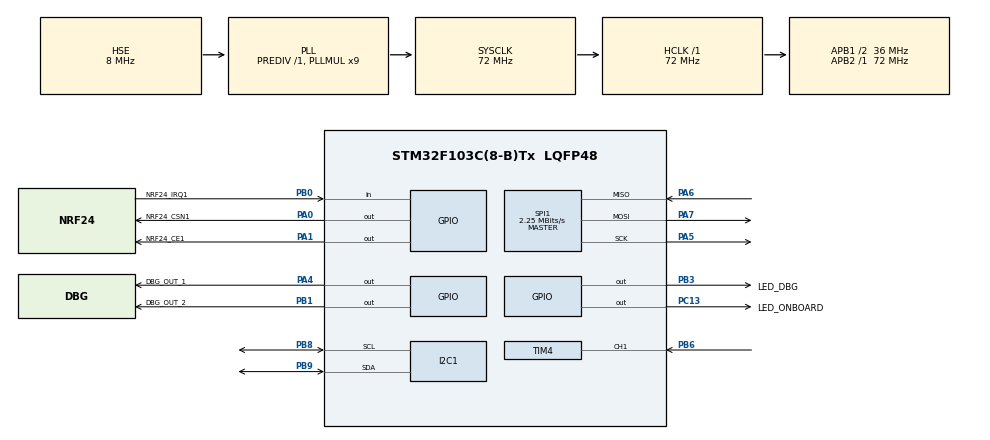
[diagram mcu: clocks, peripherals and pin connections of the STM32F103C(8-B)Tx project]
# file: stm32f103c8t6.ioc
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Mcu.Family=STM32F1
Mcu.Name=STM32F103C(8-B)Tx
Mcu.Package=LQFP48
Mcu.UserConstants=DelayCheckingPeriod,(100 - 1);envelop_timer_prescaler,(72 - 1);max_period,(65535-1)
NVIC.PriorityGroup=NVIC_PRIORITYGROUP_4
NVIC.SPI1_IRQn=true\:0\:0\:false\:false\:true
NVIC.TIM3_IRQn=true\:0\:0\:false\:false\:true
NVIC.TIM4_IRQn=true\:0\:0\:false\:false\:true
PA0-WKUP.GPIO_Label=NRF24_CSN1
PA0-WKUP.GPIO_Speed=GPIO_SPEED_FREQ_HIGH
PA0-WKUP.Signal=GPIO_Output
PA1.GPIO_Label=NRF24_CE1
PA1.GPIO_Speed=GPIO_SPEED_FREQ_HIGH
PA1.Signal=GPIO_Output
PA13.Mode=Serial_Wire
PA13.Signal=SYS_JTMS-SWDIO
PA14.Mode=Serial_Wire
PA14.Signal=SYS_JTCK-SWCLK
PA4.GPIO_Label=DBG_OUT_1
PA4.GPIO_Speed=GPIO_SPEED_FREQ_HIGH
PA4.PinState=GPIO_PIN_RESET
PA4.Signal=GPIO_Output
PA5.Mode=Full_Duplex_Master
PA5.Signal=SPI1_SCK
PA6.Mode=Full_Duplex_Master
PA6.Signal=SPI1_MISO
PA7.Mode=Full_Duplex_Master
PA7.Signal=SPI1_MOSI
PB0.GPIO_Label=NRF24_IRQ1
PB0.GPIO_PuPd=GPIO_PULLUP
PB0.Signal=GPIO_Input
PB1.GPIO_Label=DBG_OUT_2
PB1.GPIO_Speed=GPIO_SPEED_FREQ_HIGH
PB1.Signal=GPIO_Output
PB3.GPIO_Label=LED_DBG
PB3.GPIO_Speed=GPIO_SPEED_FREQ_HIGH
PB3.Signal=GPIO_Output
PB6.Signal=S_TIM4_CH1
PB8.Mode=I2C
PB8.Signal=I2C1_SCL
PB9.Mode=I2C
PB9.Signal=I2C1_SDA
PC13-TAMPER-RTC.GPIO_Label=LED_ONBOARD
PC13-TAMPER-RTC.GPIO_Speed=GPIO_SPEED_FREQ_LOW
PC13-TAMPER-RTC.Signal=GPIO_Output
PD0-OSC_IN.Mode=HSE-External-Oscillator
PD0-OSC_IN.Signal=RCC_OSC_IN
PD1-OSC_OUT.Mode=HSE-External-Oscillator
PD1-OSC_OUT.Signal=RCC_OSC_OUT
ProjectManager.HeapSize=0x200
ProjectManager.StackSize=0x400
ProjectManager.TargetToolchain=SW4STM32
RCC.ADCPresc=RCC_ADCPCLK2_DIV6
RCC.AHBFreq_Value=72000000
RCC.APB1CLKDivider=RCC_HCLK_DIV2
RCC.APB1Freq_Value=36000000
RCC.APB1TimFreq_Value=72000000
RCC.APB2Freq_Value=72000000
RCC.APB2TimFreq_Value=72000000
RCC.HCLKFreq_Value=72000000
RCC.HSIState=RCC_HSI_ON
RCC.PLLMUL=RCC_PLL_MUL9
RCC.PLLSourceVirtual=RCC_PLLSOURCE_HSE
RCC.SYSCLKFreq_VALUE=72000000
RCC.SYSCLKSource=RCC_SYSCLKSOURCE_PLLCLK
RCC.USBFreq_Value=48000000
RCC.USBPrescaler=RCC_USBCLKSOURCE_PLL_DIV1_5
SH.S_TIM4_CH1.0=TIM4_CH1,Input_Capture1_from_TI1
SH.S_TIM4_CH1.1=TIM4_CH1,Input_Capture2_from_TI1
SH.S_TIM4_CH1.2=TIM4_CH1,TriggerSource_TI1FP1
SPI1.BaudRatePrescaler=SPI_BAUDRATEPRESCALER_32
SPI1.CalculateBaudRate=2.25 MBits/s
SPI1.Mode=SPI_MODE_MASTER
TIM2.Period=71
TIM3.Period=DelayCheckingPeriod
TIM3.Prescaler=envelop_timer_prescaler
TIM3.TIM_MasterOutputTrigger=TIM_TRGO_UPDATE
TIM3.TIM_MasterSlaveMode=TIM_MASTERSLAVEMODE_DISABLE
TIM4.Channel-Input_Capture2_from_TI1=TIM_CHANNEL_2
TIM4.Period=65535
TIM4.Prescaler=envelop_timer_prescaler
TIM4.TIM_MasterOutputTrigger=TIM_TRGO_OC1
VP_CRC_VS_CRC.Mode=CRC_Activate
VP_TIM2_VS_ClockSourceINT.Mode=Internal
VP_TIM3_VS_ClockSourceINT.Mode=Internal
VP_TIM4_VS_ClockSourceINT.Mode=Internal
VP_TIM4_VS_ControllerModeReset.Mode=Reset Mode
board=stm32f103c8t6

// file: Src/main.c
/**
  ******************************************************************************
  * File Name          : main.c
  * Description        : Main program body
  ******************************************************************************
  *
  * COPYRIGHT(c) 2016 STMicroelectronics
  *
  * Redistribution and use in source and binary forms, with or without modification,
  * are permitted provided that the following conditions are met:
  *   1. Redistributions of source code must retain the above copyright notice,
  *      this list of conditions and the following disclaimer.
  *   2. Redistributions in binary form must reproduce the above copyright notice,
  *      this list of conditions and the following disclaimer in the documentation
  *      and/or other materials provided with the distribution.
  *   3. Neither the name of STMicroelectronics nor the names of its contributors
  *      may be used to endorse or promote products derived from this software
  *      without specific prior written permission.
  *
  * THIS SOFTWARE IS PROVIDED BY THE COPYRIGHT HOLDERS AND CONTRIBUTORS "AS IS"
  * AND ANY EXPRESS OR IMPLIED WARRANTIES, INCLUDING, BUT NOT LIMITED TO, THE
  * IMPLIED WARRANTIES OF MERCHANTABILITY AND FITNESS FOR A PARTICULAR PURPOSE ARE
  * DISCLAIMED. IN NO EVENT SHALL THE COPYRIGHT HOLDER OR CONTRIBUTORS BE LIABLE
  * FOR ANY DIRECT, INDIRECT, INCIDENTAL, SPECIAL, EXEMPLARY, OR CONSEQUENTIAL
  * DAMAGES (INCLUDING, BUT NOT LIMITED TO, PROCUREMENT OF SUBSTITUTE GOODS OR
  * SERVICES; LOSS OF USE, DATA, OR PROFITS; OR BUSINESS INTERRUPTION) HOWEVER
  * CAUSED AND ON ANY THEORY OF LIABILITY, WHETHER IN CONTRACT, STRICT LIABILITY,
  * OR TORT (INCLUDING NEGLIGENCE OR OTHERWISE) ARISING IN ANY WAY OUT OF THE USE
  * OF THIS SOFTWARE, EVEN IF ADVISED OF THE POSSIBILITY OF SUCH DAMAGE.
  *
  ******************************************************************************
  */
#include "stm32f1xx_hal.h"

/* USER CODE BEGIN Includes */
#include <stdbool.h>
#include "infrared.h"
#include "sensor.h"
#include "se8r01.h"
#include "MPU6050.h"
#include "common.h"
#define USE_OLD_MAPPING 1

// TODO: cleanup when done debugging
/* USER CODE END Includes */

CRC_HandleTypeDef hcrc;

I2C_HandleTypeDef hi2c1;

SPI_HandleTypeDef hspi1;

TIM_HandleTypeDef htim2;
TIM_HandleTypeDef htim3;
TIM_HandleTypeDef htim4;

/* USER CODE BEGIN PV */
/* Private variables ---------------------------------------------------------*/
/// parameters for receiver ===================
const GPIO_TypeDef * IR_IN_Gpio_Port = GPIOB;
const uint16_t IR_IN_Gpio_Pin = GPIO_PIN_10;

TIM_HandleTypeDef* ptim_input_capture = &htim4;
TIM_HandleTypeDef* ptim_data_read = &htim3;
TIM_HandleTypeDef* phtim_delay = &htim2;

extern const bool _is_direct_logic;
const bool _debug = true;

extern GPIO_TypeDef * GPIO_LED_PORT;
extern uint16_t GPIO_LED_PIN;
/// ===========================================

/* USER CODE END PV */

void SystemClock_Config(void);
void Error_Handler(void);
static void MX_GPIO_Init(void);
static void MX_CRC_Init(void);
static void MX_SPI1_Init(void);
static void MX_TIM3_Init(void);
static void MX_TIM4_Init(void);
static void MX_TIM2_Init(void);
static void MX_I2C1_Init(void);

/* USER CODE BEGIN PFP */
/* Private function prototypes -----------------------------------------------*/
HAL_StatusTypeDef HAL_TIM_IC_PWM_Start_IT (const TIM_HandleTypeDef *htim);
HAL_StatusTypeDef HAL_TIM_IC_PWM_Stop_IT (const TIM_HandleTypeDef *htim);
void send_data_uart();
void setup_infrared_input_gpio();

extern uint8_t rx_buf[TX_PLOAD_WIDTH];
extern uint8_t tx_buf[TX_PLOAD_WIDTH];
extern RadioMessage rx_message;
extern RadioMessage tx_message;

extern NRF_Module default_module;
extern NRF_Module data_module;

extern RadioDevInfo radiodevinfo;
extern SensorData sensordata;
BeamerData beamerdata = {0};
IMUData imudata = {0};

/* USER CODE END PFP */

/* USER CODE BEGIN 0 */
/// ======================= USART stuff =======================
HAL_StatusTypeDef status;
extern DataFrame_t rx_data_frame;

const char mode = 'r'; // 't'
/* USER CODE END 0 */

int main(void)
{

  /* MCU Configuration----------------------------------------------------------*/
  /* Reset of all peripherals, Initializes the Flash interface and the Systick. */
  HAL_Init();

  /* Configure the system clock */
  SystemClock_Config();

  /* Initialize all configured peripherals */
  MX_GPIO_Init();
  MX_CRC_Init();
  MX_SPI1_Init();
  MX_TIM3_Init();
  MX_TIM4_Init();
  MX_TIM2_Init();
  MX_I2C1_Init();

  /* USER CODE BEGIN 2 */
  setup_infrared_input_gpio();

  bool use_radio = true;

  if(use_radio){
    configure_gpio_radio();
  }

    //TODO: setting the timer. merge with TIM_Init

    //// start usec delay timer
    HAL_TIM_Base_Start(&htim2);

    bool enable_IR_timers = true;//TODO
    if(enable_IR_timers){
        setup_ic_timer();
        HAL_TIM_Base_Start_IT(ptim_data_read);
        HAL_TIM_IC_PWM_Start_IT(ptim_input_capture);
    }
  /* USER CODE END 2 */

  /* Infinite loop */
  /* USER CODE BEGIN WHILE */

    // use identical bytes
    bool is_transmitter = (mode =='t');
    bool is_receiver = !is_transmitter;

    if(use_radio){
      setup(&default_module);
    }

    //nrf_without_this_interrupts_not_work();
    HAL_Delay(100);

    if (MPU6050_testConnection()){
        HAL_GPIO_WritePin (LED_ONBOARD_GPIO_Port, LED_ONBOARD_Pin, HIGH);
    }
    else{
          HAL_GPIO_WritePin (LED_ONBOARD_GPIO_Port, LED_ONBOARD_Pin, LOW);
    }

    while (1)
    {

        /*
        GPIO_PinState state = HAL_GPIO_ReadPin (GPIOB, GPIO_PIN_6);
        if(state == HIGH){
            HAL_GPIO_WritePin (GPIOB, GPIO_PIN_11, HIGH);
            HAL_GPIO_WritePin (LED_ONBOARD_GPIO_Port, LED_ONBOARD_Pin, HIGH);
        }
        else{
            HAL_GPIO_WritePin (GPIOB, GPIO_PIN_11, LOW);
            HAL_GPIO_WritePin (LED_ONBOARD_GPIO_Port, LED_ONBOARD_Pin, HIGH);
        }
        */

        if(use_radio)
        {
            if(is_receiver){
                RXX(&default_module);// - this is called on IRQ
            }
            else if(is_transmitter){
                //=================== prepare message for sending
                // Determine source of packet
                radio_tx_set_message_header(WhoAmI_Sensor, Dest_UsbDevice,Typ_SensorData);

                SingleBeamerData singlebeamdata;
                singlebeamdata.angle = 124;
                singlebeamdata.beamer_id = 1;

                beamerdata.beamer_data_array[0] = singlebeamdata;

                radio_tx_set_sensordata(&sensordata);
                //=====================

                TXX(&default_module);
                HAL_Delay(30);
            }
        }

  /* USER CODE END WHILE */

    }

}

/** System Clock Configuration
*/
void SystemClock_Config(void)
{

  RCC_OscInitTypeDef RCC_OscInitStruct;
  RCC_ClkInitTypeDef RCC_ClkInitStruct;

  RCC_OscInitStruct.OscillatorType = RCC_OSCILLATORTYPE_HSE;
  RCC_OscInitStruct.HSEState = RCC_HSE_ON;
  RCC_OscInitStruct.HSEPredivValue = RCC_HSE_PREDIV_DIV1;
  RCC_OscInitStruct.PLL.PLLState = RCC_PLL_ON;
  RCC_OscInitStruct.PLL.PLLSource = RCC_PLLSOURCE_HSE;
  RCC_OscInitStruct.PLL.PLLMUL = RCC_PLL_MUL9;
  if (HAL_RCC_OscConfig(&RCC_OscInitStruct) != HAL_OK)
  {
    Error_Handler();
  }

  RCC_ClkInitStruct.ClockType = RCC_CLOCKTYPE_HCLK|RCC_CLOCKTYPE_SYSCLK
                              |RCC_CLOCKTYPE_PCLK1|RCC_CLOCKTYPE_PCLK2;
  RCC_ClkInitStruct.SYSCLKSource = RCC_SYSCLKSOURCE_PLLCLK;
  RCC_ClkInitStruct.AHBCLKDivider = RCC_SYSCLK_DIV1;
  RCC_ClkInitStruct.APB1CLKDivider = RCC_HCLK_DIV2;
  RCC_ClkInitStruct.APB2CLKDivider = RCC_HCLK_DIV1;
  if (HAL_RCC_ClockConfig(&RCC_ClkInitStruct, FLASH_LATENCY_2) != HAL_OK)
  {
    Error_Handler();
  }

  HAL_SYSTICK_Config(HAL_RCC_GetHCLKFreq()/1000);

  HAL_SYSTICK_CLKSourceConfig(SYSTICK_CLKSOURCE_HCLK);

  /* SysTick_IRQn interrupt configuration */
  HAL_NVIC_SetPriority(SysTick_IRQn, 0, 0);
}

/* CRC init function */
static void MX_CRC_Init(void)
{

  hcrc.Instance = CRC;
  if (HAL_CRC_Init(&hcrc) != HAL_OK)
  {
    Error_Handler();
  }

}

/* I2C1 init function */
static void MX_I2C1_Init(void)
{

  hi2c1.Instance = I2C1;
  hi2c1.Init.ClockSpeed = 100000;
  hi2c1.Init.DutyCycle = I2C_DUTYCYCLE_2;
  hi2c1.Init.OwnAddress1 = 0;
  hi2c1.Init.AddressingMode = I2C_ADDRESSINGMODE_7BIT;
  hi2c1.Init.DualAddressMode = I2C_DUALADDRESS_DISABLE;
  hi2c1.Init.OwnAddress2 = 0;
  hi2c1.Init.GeneralCallMode = I2C_GENERALCALL_DISABLE;
  hi2c1.Init.NoStretchMode = I2C_NOSTRETCH_DISABLE;
  if (HAL_I2C_Init(&hi2c1) != HAL_OK)
  {
    Error_Handler();
  }

}

/* SPI1 init function */
static void MX_SPI1_Init(void)
{

  hspi1.Instance = SPI1;
  hspi1.Init.Mode = SPI_MODE_MASTER;
  hspi1.Init.Direction = SPI_DIRECTION_2LINES;
  hspi1.Init.DataSize = SPI_DATASIZE_8BIT;
  hspi1.Init.CLKPolarity = SPI_POLARITY_LOW;
  hspi1.Init.CLKPhase = SPI_PHASE_1EDGE;
  hspi1.Init.NSS = SPI_NSS_SOFT;
  hspi1.Init.BaudRatePrescaler = SPI_BAUDRATEPRESCALER_4;
  hspi1.Init.FirstBit = SPI_FIRSTBIT_MSB;
  hspi1.Init.TIMode = SPI_TIMODE_DISABLE;
  hspi1.Init.CRCCalculation = SPI_CRCCALCULATION_DISABLE;
  hspi1.Init.CRCPolynomial = 10;
  if (HAL_SPI_Init(&hspi1) != HAL_OK)
  {
    Error_Handler();
  }

}

/* TIM2 init function */
static void MX_TIM2_Init(void)
{

  TIM_ClockConfigTypeDef sClockSourceConfig;
  TIM_MasterConfigTypeDef sMasterConfig;

  htim2.Instance = TIM2;
  htim2.Init.Prescaler = 0;
  htim2.Init.CounterMode = TIM_COUNTERMODE_UP;
  htim2.Init.Period = 71;
  htim2.Init.ClockDivision = TIM_CLOCKDIVISION_DIV1;
  if (HAL_TIM_Base_Init(&htim2) != HAL_OK)
  {
    Error_Handler();
  }

  sClockSourceConfig.ClockSource = TIM_CLOCKSOURCE_INTERNAL;
  if (HAL_TIM_ConfigClockSource(&htim2, &sClockSourceConfig) != HAL_OK)
  {
    Error_Handler();
  }

  sMasterConfig.MasterOutputTrigger = TIM_TRGO_RESET;
  sMasterConfig.MasterSlaveMode = TIM_MASTERSLAVEMODE_DISABLE;
  if (HAL_TIMEx_MasterConfigSynchronization(&htim2, &sMasterConfig) != HAL_OK)
  {
    Error_Handler();
  }

}

/* TIM3 init function */
static void MX_TIM3_Init(void)
{

  TIM_ClockConfigTypeDef sClockSourceConfig;
  TIM_MasterConfigTypeDef sMasterConfig;

  htim3.Instance = TIM3;
  htim3.Init.Prescaler = (72-1);
  htim3.Init.CounterMode = TIM_COUNTERMODE_UP;
  htim3.Init.Period = 100-1;
  htim3.Init.ClockDivision = TIM_CLOCKDIVISION_DIV1;
  if (HAL_TIM_Base_Init(&htim3) != HAL_OK)
  {
    Error_Handler();
  }

  sClockSourceConfig.ClockSource = TIM_CLOCKSOURCE_INTERNAL;
  if (HAL_TIM_ConfigClockSource(&htim3, &sClockSourceConfig) != HAL_OK)
  {
    Error_Handler();
  }

  sMasterConfig.MasterOutputTrigger = TIM_TRGO_UPDATE;
  sMasterConfig.MasterSlaveMode = TIM_MASTERSLAVEMODE_DISABLE;
  if (HAL_TIMEx_MasterConfigSynchronization(&htim3, &sMasterConfig) != HAL_OK)
  {
    Error_Handler();
  }

}

/* TIM4 init function */
static void MX_TIM4_Init(void)
{

  TIM_ClockConfigTypeDef sClockSourceConfig;
  TIM_SlaveConfigTypeDef sSlaveConfig;
  TIM_MasterConfigTypeDef sMasterConfig;
  TIM_IC_InitTypeDef sConfigIC;

  htim4.Instance = TIM4;
  htim4.Init.Prescaler = 72-1;
  htim4.Init.CounterMode = TIM_COUNTERMODE_UP;
  htim4.Init.Period = 65535;
  htim4.Init.ClockDivision = TIM_CLOCKDIVISION_DIV1;
  if (HAL_TIM_Base_Init(&htim4) != HAL_OK)
  {
    Error_Handler();
  }

  sClockSourceConfig.ClockSource = TIM_CLOCKSOURCE_INTERNAL;
  if (HAL_TIM_ConfigClockSource(&htim4, &sClockSourceConfig) != HAL_OK)
  {
    Error_Handler();
  }

  if (HAL_TIM_IC_Init(&htim4) != HAL_OK)
  {
    Error_Handler();
  }

  sSlaveConfig.SlaveMode = TIM_SLAVEMODE_RESET;
  sSlaveConfig.InputTrigger = TIM_TS_TI1FP1;
  sSlaveConfig.TriggerPolarity = TIM_INPUTCHANNELPOLARITY_FALLING;
  sSlaveConfig.TriggerFilter = 0;
  if (HAL_TIM_SlaveConfigSynchronization(&htim4, &sSlaveConfig) != HAL_OK)
  {
    Error_Handler();
  }

  sMasterConfig.MasterOutputTrigger = TIM_TRGO_OC1;
  sMasterConfig.MasterSlaveMode = TIM_MASTERSLAVEMODE_DISABLE;
  if (HAL_TIMEx_MasterConfigSynchronization(&htim4, &sMasterConfig) != HAL_OK)
  {
    Error_Handler();
  }

  sConfigIC.ICPolarity = TIM_INPUTCHANNELPOLARITY_FALLING;
  sConfigIC.ICSelection = TIM_ICSELECTION_DIRECTTI;
  sConfigIC.ICPrescaler = TIM_ICPSC_DIV1;
  sConfigIC.ICFilter = 0;
  if (HAL_TIM_IC_ConfigChannel(&htim4, &sConfigIC, TIM_CHANNEL_1) != HAL_OK)
  {
    Error_Handler();
  }

  sConfigIC.ICPolarity = TIM_INPUTCHANNELPOLARITY_RISING;
  sConfigIC.ICSelection = TIM_ICSELECTION_INDIRECTTI;
  if (HAL_TIM_IC_ConfigChannel(&htim4, &sConfigIC, TIM_CHANNEL_2) != HAL_OK)
  {
    Error_Handler();
  }

}

/** Configure pins as
        * Analog
        * Input
        * Output
        * EVENT_OUT
        * EXTI
*/
static void MX_GPIO_Init(void)
{

  GPIO_InitTypeDef GPIO_InitStruct;

  /* GPIO Ports Clock Enable */
  __HAL_RCC_GPIOC_CLK_ENABLE();
  __HAL_RCC_GPIOD_CLK_ENABLE();
  __HAL_RCC_GPIOA_CLK_ENABLE();
  __HAL_RCC_GPIOB_CLK_ENABLE();

  /*Configure GPIO pin Output Level */
  HAL_GPIO_WritePin(LED_ONBOARD_GPIO_Port, LED_ONBOARD_Pin, GPIO_PIN_RESET);

  /*Configure GPIO pin Output Level */
  HAL_GPIO_WritePin(GPIOB, GPIO_PIN_11|LED_DBG_Pin, GPIO_PIN_RESET);

  /*Configure GPIO pin : LED_ONBOARD_Pin */
  GPIO_InitStruct.Pin = LED_ONBOARD_Pin;
  GPIO_InitStruct.Mode = GPIO_MODE_OUTPUT_PP;
  GPIO_InitStruct.Speed = GPIO_SPEED_FREQ_LOW;
  HAL_GPIO_Init(LED_ONBOARD_GPIO_Port, &GPIO_InitStruct);

  /*Configure GPIO pin : PB10 */
  GPIO_InitStruct.Pin = GPIO_PIN_10;
  GPIO_InitStruct.Mode = GPIO_MODE_INPUT;
  GPIO_InitStruct.Pull = GPIO_NOPULL;
  HAL_GPIO_Init(GPIOB, &GPIO_InitStruct);

  /*Configure GPIO pin : PB11 */
  GPIO_InitStruct.Pin = GPIO_PIN_11;
  GPIO_InitStruct.Mode = GPIO_MODE_OUTPUT_PP;
  GPIO_InitStruct.Speed = GPIO_SPEED_FREQ_HIGH;
  HAL_GPIO_Init(GPIOB, &GPIO_InitStruct);

  /*Configure GPIO pin : LED_DBG_Pin */
  GPIO_InitStruct.Pin = LED_DBG_Pin;
  GPIO_InitStruct.Mode = GPIO_MODE_OUTPUT_PP;
  GPIO_InitStruct.Speed = GPIO_SPEED_FREQ_HIGH;
  HAL_GPIO_Init(LED_DBG_GPIO_Port, &GPIO_InitStruct);

}

/* USER CODE BEGIN 4 */
HAL_StatusTypeDef HAL_TIM_IC_PWM_Start_IT (const TIM_HandleTypeDef *htim)
{
    /* Check the parameters */
    assert_param(IS_TIM_CCX_INSTANCE(htim->Instance, TIM_CHANNEL_1));
    assert_param(IS_TIM_CCX_INSTANCE(htim->Instance, TIM_CHANNEL_2));

    /* Enable the TIM Capture/Compare 1 interrupt */
    __HAL_TIM_ENABLE_IT(htim, TIM_IT_CC1);
    /* Enable the TIM Capture/Compare 2 interrupt */
    __HAL_TIM_ENABLE_IT(htim, TIM_IT_CC2);

    /* Enable the Input Capture channel */
    TIM_CCxChannelCmd(htim->Instance, TIM_CHANNEL_1, TIM_CCx_ENABLE);
    TIM_CCxChannelCmd(htim->Instance, TIM_CHANNEL_2, TIM_CCx_ENABLE);

    /* Enable the Peripheral */
    __HAL_TIM_ENABLE(htim);

    /* Return function status */
    return HAL_OK;
}
HAL_StatusTypeDef HAL_TIM_IC_PWM_Stop_IT (const TIM_HandleTypeDef *htim)
{
    assert_param(IS_TIM_CCX_INSTANCE(htim->Instance, TIM_CHANNEL_1));
    assert_param(IS_TIM_CCX_INSTANCE(htim->Instance, TIM_CHANNEL_2));

    __HAL_TIM_DISABLE_IT(htim, TIM_IT_CC1);
    __HAL_TIM_DISABLE_IT(htim, TIM_IT_CC2);

    /* Disable the Input Capture channel */
    TIM_CCxChannelCmd(htim->Instance, TIM_CHANNEL_1, TIM_CCx_DISABLE);
    TIM_CCxChannelCmd(htim->Instance, TIM_CHANNEL_2, TIM_CCx_DISABLE);

    /* Disable the Peripheral */
    __HAL_TIM_DISABLE(htim);

    /* Return function status */
    return HAL_OK;
}

void nrf_receive_callback()
{
    HAL_GPIO_TogglePin(GPIOC,GPIO_PIN_13);
}

void setup_infrared_input_gpio()
{
    GPIO_InitTypeDef GPIO_InitStruct;

    /*Configure GPIO pin : LED_ONBOARD_Pin */
    GPIO_InitStruct.Pin = IR_IN_Gpio_Pin;
    GPIO_InitStruct.Mode = GPIO_MODE_INPUT;
    GPIO_InitStruct.Pull = GPIO_NOPULL;
    HAL_GPIO_Init(IR_IN_Gpio_Port, &GPIO_InitStruct);

}
/*
void HAL_TIM_PeriodElapsedCallback(TIM_HandleTypeDef *htim)
{
    // handle tim2 event since it is delay event
  if(htim->Instance == TIM2)
  {
      if(us_cnt > us_delay_value - 1){
        HAL_TIM_Base_Stop_IT(&htim2);
      }
  }
}
*/

/* USER CODE END 4 */

void Error_Handler(void)
{
  while(1)
  {
  }
}

/************************ (C) COPYRIGHT STMicroelectronics *****END OF FILE****/
